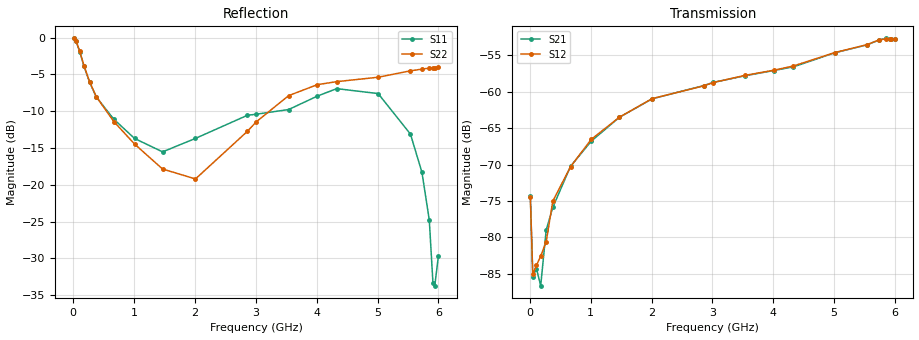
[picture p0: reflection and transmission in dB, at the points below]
!Agilent Technologies,N5230A,MY45001650,A.07.50.48
!Agilent N5230A: A.07.50.48
!Date: Saturday, July 08, 2017 15:51:48
!Correction: S11(Full 2 Port(1,2))
!S21(Full 2 Port(1,2))
!S12(Full 2 Port(1,2))
!S22(Full 2 Port(1,2))
!S2P File: Measurements: S11, S21, S12, S22:
# Hz S  dB  R 50
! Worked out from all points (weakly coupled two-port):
!   600 points, 10 MHz to 6 GHz, reference 50 ohm
!   highest |S21| = -52.69 dB at 5.85 GHz (marker M1); lowest = -86.6 dB at 180 MHz (marker M2)
!   lowest |S11| = -33.7 dB at 5.94 GHz (marker M3), VSWR 1.04, Z = 48.2 - j0.863 ohm
!   |S11| at or under -10 dB: 551.2 MHz to 3.399 GHz (2.847 GHz wide, 144 % of centre); 3.406 GHz to 3.469 GHz (62.81 MHz wide, 1.83 % of centre); 5.331 GHz to end of sweep
!   |S22| runs from -19.7 to -0.1 dB; largest |S21 - S12| = 0.0003
!   S11 on the Smith chart (normalised r, x): 10 MHz: 2, -19; 110 MHz: 0.49, -1.80; 380 MHz: 0.53, -0.41; 2.86 GHz: 0.60, +0.27; 4.33 GHz: 2.52, +0.50; 6 GHz: 0.96, +0.05
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1e7  -0.11 -6.0  -74.27 -6.8  -74.51 -108.9  -0.11 -5.5
5e7  -0.51 -27.7  -85.39 97.8  -85.09 131.1  -0.48 -25.4
1.1e8  -1.94 -55.4  -84.29 -37.5  -83.84 40.3  -1.88 -50.5
1.8e8  -3.91 -79.6  -86.63 114.5  -82.56 129.9  -3.85 -72.3
2.7e8  -6.03 -102.5  -78.99 97.4  -80.59 104.2  -5.97 -92.0
3.8e8  -8.06 -123.6  -75.86 82.7  -75.01 84.3  -8.02 -108.8
6.7e8  -11.10 -161.0  -70.25 47.7  -70.30 46.7  -11.42 -137.2
1.01e9  -13.71 176.3  -66.80 14.0  -66.55 14.5  -14.47 -154.4
1.47e9  -15.53 166.6  -63.54 -29.3  -63.52 -29.2  -17.86 -170.6
2.01e9  -13.70 172.2  -60.99 -81.2  -60.96 -81.2  -19.21 -171.0
2.86e9  -10.57 135.9  -59.16 -163.1  -59.20 -163.4  -12.76 172.8
3.01e9  -10.41 123.9  -58.74 -177.1  -58.76 -176.5  -11.44 168.7
3.54e9  -9.78 74.0  -57.82 132.0  -57.76 132.2  -7.89 154.5
4.01e9  -7.96 29.9  -57.10 88.6  -57.06 88.4  -6.40 140.6
4.33e9  -6.94 10.0  -56.60 63.6  -56.48 63.9  -5.99 130.7
5.01e9  -7.61 -21.5  -54.67 9.4  -54.64 9.7  -5.39 103.2
5.54e9  -13.11 -47.9  -53.58 -34.5  -53.55 -34.4  -4.52 76.4
5.73e9  -18.33 -60.4  -52.94 -48.7  -52.92 -49.0  -4.29 66.0
5.85e9  -24.79 -75.2  -52.69 -61.6  -52.76 -61.2  -4.15 59.8
5.91e9  -33.36 -115.3  -52.74 -67.0  -52.76 -66.8  -4.08 57.4
5.94e9  -33.71 -154.3  -52.77 -69.5  -52.78 -69.4  -4.08 55.5
6e9  -29.65 131.2  -52.73 -74.5  -52.77 -74.1  -3.99 52.3
